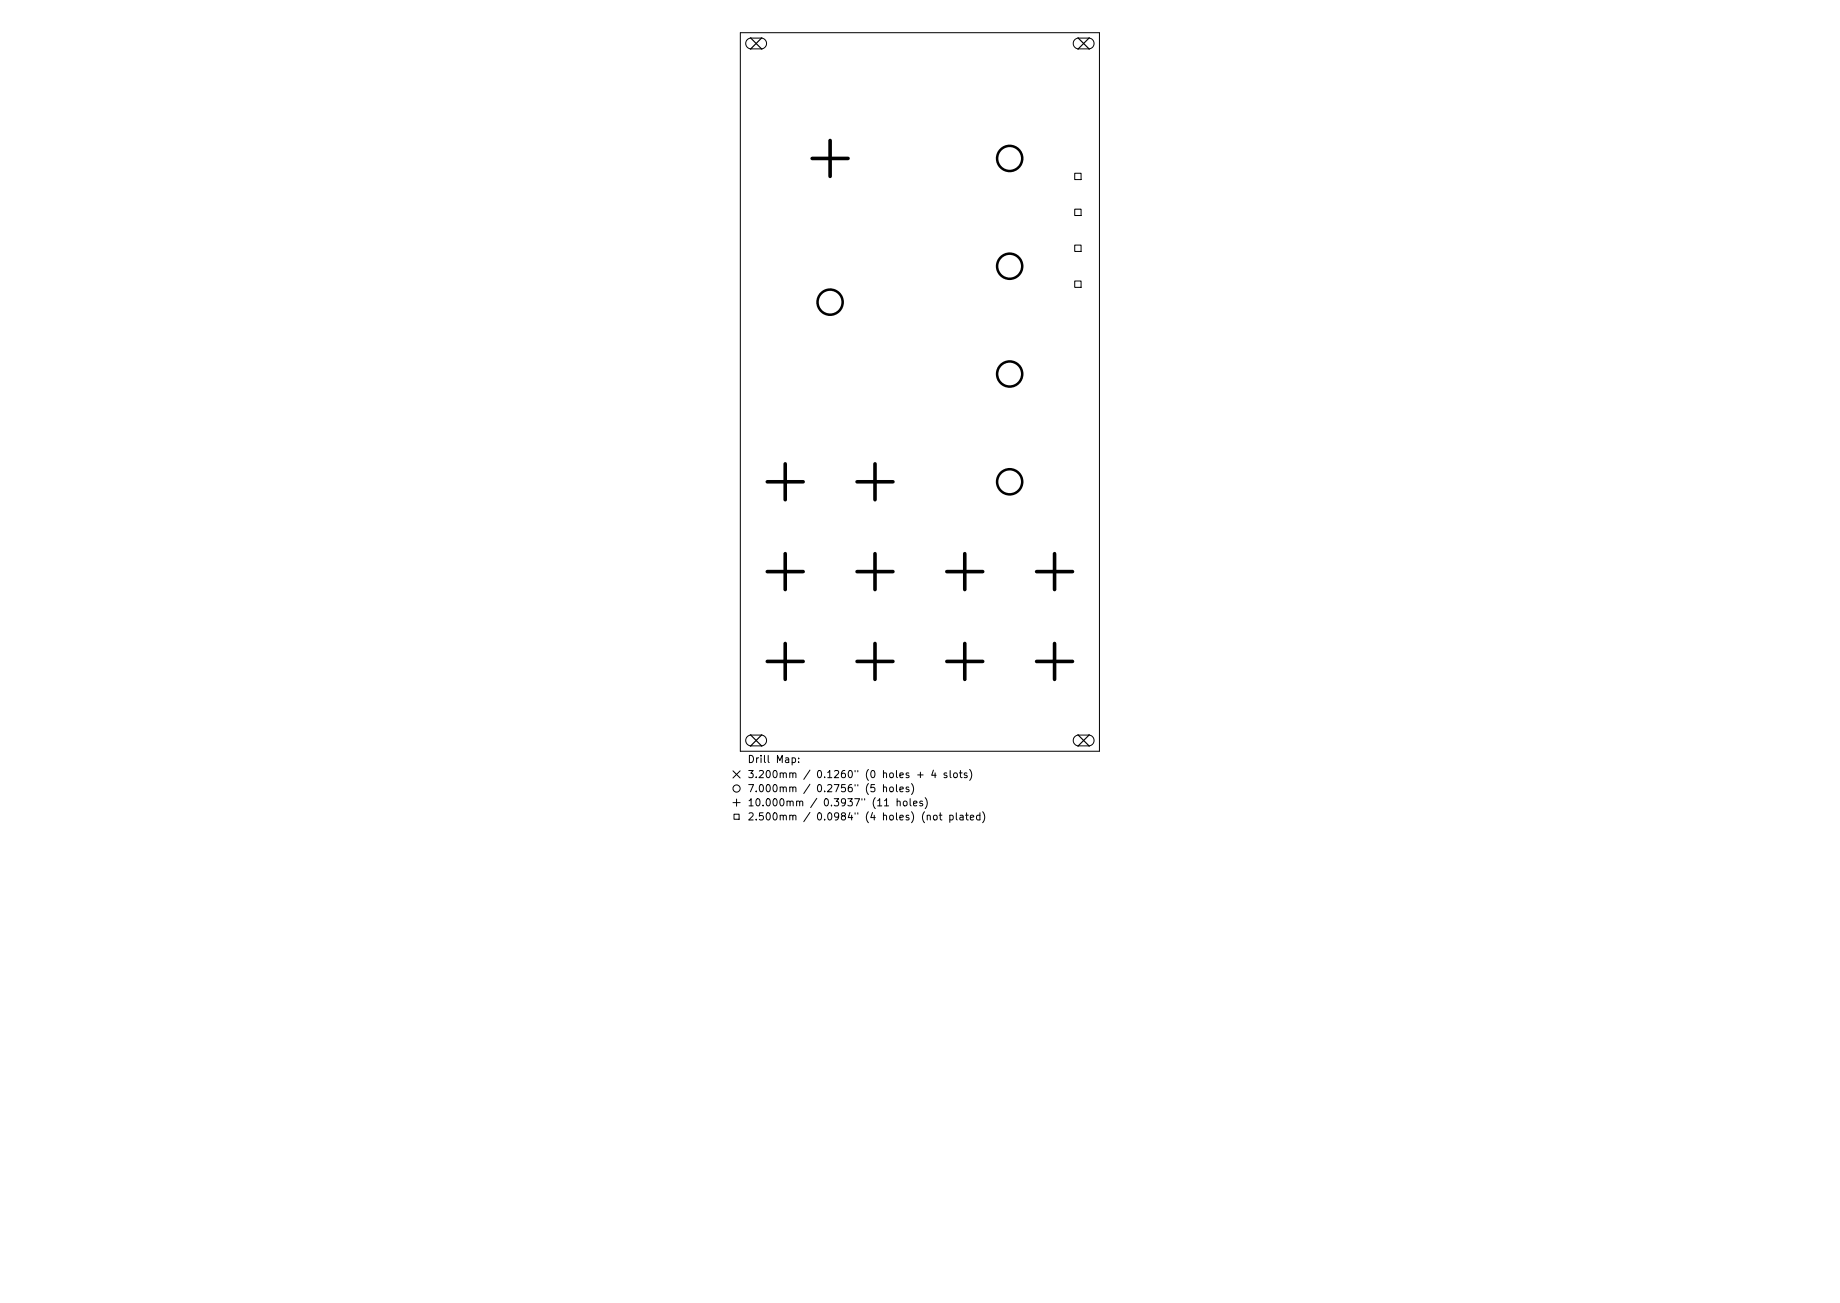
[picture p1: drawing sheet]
<svg xmlns="http://www.w3.org/2000/svg" width="297mm" height="210mm" viewBox="0 0 297 210" stroke-linecap="round" stroke-linejoin="round" font-family="sans-serif">
<defs><g id="words">
<g font-size="1.6">
<text x="120.6" y="123.1">Drill Map:</text>
<text x="120.6" y="125.5">3.200mm / 0.1260&quot; (0 holes + 4 slots)</text>
<text x="120.6" y="127.8">7.000mm / 0.2756&quot; (5 holes)</text>
<text x="120.6" y="130.1">10.000mm / 0.3937&quot; (11 holes)</text>
<text x="120.6" y="132.4">2.500mm / 0.0984&quot; (4 holes) (not plated)</text>
</g>
</g></defs>
<g fill="none" stroke="#000" stroke-width=".16">
<path d="M119.5 5.3h58v115.9h-58zM120.6 6.4l.6-.2 1.7-.1a.87 .87 0 0 1 .8 .9 .87 .87 0 0 1-.8 .9h-1.6a.87 .87 0 0 1-.8-.6 .87 .87 0 0 1 .1-.9zM173.5 6.4l.5-.2 1.7-.1a.87 .87 0 0 1 .9 .9 .87 .87 0 0 1-.9 .9h-1.6a.87 .87 0 0 1-.8-.6 .87 .87 0 0 1 .2-.9zM173.5 28h1v1h-1zM173.5 33.8h1v1h-1zM173.5 39.5h1v1.1h-1zM173.5 45.3h1v1.1h-1zM120.6 118.9l.6-.3h1.7a.87 .87 0 0 1 .8 .9 .87 .87 0 0 1-.8 .9h-1.6a.87 .87 0 0 1-.8-.6 .87 .87 0 0 1 .1-.9zM173.5 118.9l.5-.3h1.7a.87 .87 0 0 1 .9 .9 .87 .87 0 0 1-.9 .9h-1.6a.87 .87 0 0 1-.8-.6 .87 .87 0 0 1 .2-.9zM118.3 124.4l1.2 1.1M118.3 129.5h1.2M118.5 131.4h.8v.8h-.8z"/>
<path d="M118.9 128.9v1.2M119.5 124.4l-1.2 1.1M127.9 122.3h.3l.2 .2-.1 .5h-.4M128.9 122.9v.2M128.9 122.3v.1M142.6 127.1l.2-.1h.3v.8M142.6 126.6v1.2M142.8 130h.7M143.7 127.1l.1-.1 .4 .1v.4l-.1 .2-.3 .1-.1-.1zM144.7 126.6v1l.2 .2M144.8 129.4l.2-.1h.3v.7M144.8 128.9v1.1"/>
<path d="M145.3 127.4l.5-.1v-.3h-.4l-.1 .2v.5h.5M145.9 129.4l.1-.1 .4 .1v.4l-.1 .2h-.3l-.1-.1zM146.7 127h-.3l-.1 .2v.1l.4 .1v.3h-.4M146.9 128.9v1l.2 .1M147.1 126.4a1.33 1.33 0 0 1 0 1.8M147.5 129.7l.5-.2v-.2h-.4l-.1 .1v.6h.5M148.1 125h.9M148.6 124.6v.9M148.9 129.3h-.3l-.1 .1v.2l.4 .1v.3h-.4M149.4 128.7a1.33 1.33 0 0 1 0 1.8M149.7 131.7l.2-.2 .2 .1 .1 .7M150.7 124.3l-.3 .8h.7"/>
<path d="M150.8 131.6l.3-.1 .2 .3v.3l-.2 .2h-.3l-.1-.2zM151 124.7v.8M151.6 131.5h.5M151.8 131.2v.9l.3 .2M152.8 124.8l-.2-.1-.2 .2 .1 .1 .3 .2v.2h-.4M153.3 131.6l.4-.1 .2 .3-.1 .5h-.5M153.3 131.5v1.2M153.4 124.3v1l.2 .2M154 124.8l.2-.1 .3 .1v.5l-.1 .1-.2 .1-.2-.1zM154.4 131.2v.9l.1 .2M154.9 124.7h.4M155 131.6h.4l.1 .7"/>
<path d="M155 124.3v1l.3 .2M155.5 131.8l-.4 .1-.2 .1 .2 .3h.4M155.9 131.5h.4M156 131.2v.9l.3 .2M156.1 124.8l-.3-.1-.1 .2v.1l.4 .2v.2h-.4M156.5 124.2a1.33 1.33 0 0 1 0 1.7M156.6 131.9l.6-.1-.1-.2-.3-.1-.2 .2 .1 .6h.4M158.2 131.6l-.3-.1-.3 .3 .2 .5h.4M158.2 131.2v1.1M158.6 131a1.33 1.33 0 0 1 0 1.8"/>
<circle cx="118.9" cy="127.2" r=".58"/>
</g>
<path d="M121.1 6.1l1.9 1.8M123 6.1l-1.9 1.8M174 6.1l1.9 1.8M175.9 6.1l-1.9 1.8M121.1 118.6l1.9 1.8M123 118.6l-1.9 1.8M174 118.6l1.9 1.8M175.9 118.6l-1.9 1.8" fill="none" stroke="#000" stroke-width=".19"/>
<g fill="none" stroke="#000" stroke-width=".41">
<circle cx="163" cy="25.6" r="2.03"/>
<circle cx="134" cy="48.8" r="2.03"/>
<circle cx="163" cy="43" r="2.03"/>
<circle cx="163" cy="60.4" r="2.03"/>
<circle cx="163" cy="77.7" r="2.03"/>
</g>
<g fill="none" stroke="#000" stroke-width=".58">
<path d="M131.1 25.6h5.8M134 22.7v5.8M123.9 77.7h5.8M126.8 74.8v5.8M138.4 77.7h5.8M141.3 74.8v5.8M123.9 92.2h5.8M126.8 89.3v5.8M138.4 92.2h5.8M141.3 89.3v5.8M152.8 92.2h5.8M155.7 89.3v5.8"/>
<path d="M167.3 92.2h5.8M170.2 89.3v5.8M123.9 106.7h5.8M126.8 103.8v5.8M138.4 106.7h5.8M141.3 103.8v5.8M152.8 106.7h5.8M155.7 103.8v5.8M167.3 106.7h5.8M170.2 103.8v5.8"/>
</g>
<use href="#words"/>
</svg>
